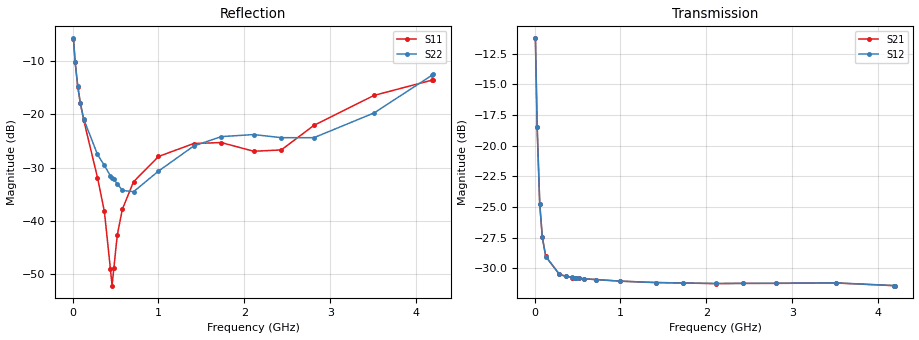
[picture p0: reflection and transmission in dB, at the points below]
! Integrated Device Technology
! Corporate Headquarters
! 6024 Silver Creek Valley Road
! San Jose, CA 95138  USA
! Phone:  1-408-284-8200
! Toll Free:  1-800-223-1366
! Webpage:  http://www.idt.com/
! Timing and RF Division
! 515 Groton Road, Suite 102
! Westford, MA 01886-6024
! Device:  F1950
! Description: 7-bit 0.25 dB Digital Step Attenuator
! Frequency:  150.0 -  4000.00 MHz
! Package:  4x4 mm Thin QFN Plastic Package: 24 pin
! Ports:  2 RF, 12 DC
!  Pin  1  = D0
!  Pin  2  = VDD
!  Pin  3  = Vmode
!  Pin  4  = GND
!  Pin  5  = RF1  =  Port 1
!  Pin  6  = GND
!  Pin  7  = GND
!  Pin  8  = GND
!  Pin  9  = GND
!  Pin 10  = GND
!  Pin 11  = GND
!  Pin 12  = GND
!  Pin 13  = GND
!  Pin 14  = RF2  =  Port 2
!  Pin 15  = GND
!  Pin 16  = LE
!  Pin 17  = CLK
!  Pin 18  = DATE
!  Pin 19  = D6
!  Pin 20  = D5
!  Pin 21  = D4
!  Pin 22  = D3
!  Pin 23  = D2
!  Pin 24  = D1
! State:  120
! Atten State:  30.00 dB
! Voltage:  +5.00 Volts
! Current:  Not Measured mA
! Data:  The device was measured on a the F195X evaluation board which has
!  individual transmission lines to the RF pins.  Data was collected
!  using a calibrated network analyzer.  The evaluation board was
!  de-embedded using a TRL calibration technique.
!  The reference plane is the edge of the package pin.
! Misc:  Board 2019
!  Action Tracker AT0250
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# GHz S dB R 50
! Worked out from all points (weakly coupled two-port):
!   420 points, 10 MHz to 4.2 GHz, reference 50 ohm
!   highest |S21| = -11.24 dB at 10 MHz (marker M1); lowest = -31.4 dB at 4.19 GHz (marker M2)
!   lowest |S11| = -52.2 dB at 460 MHz (marker M3), VSWR 1.00, Z = 49.8 - j0.108 ohm
!   |S11| at or under -10 dB: 28.84 MHz to end of sweep
!   |S22| runs from -34.8 to -5.7 dB; largest |S21 - S12| = 6.9e-05
!   S11 on the Smith chart (normalised r, x): 10 MHz: 2.05, -1.36; 30 MHz: 1.25, -0.68; 60 MHz: 1.10, -0.37; 290 MHz: 1.01, -0.05; 4.2 GHz: 0.68, +0.17
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0.01  -5.78 -28.3  -11.24 -39.9  -11.24 -39.9  -5.72 -29.3
0.03  -10.24 -52.8  -18.43 -66.2  -18.43 -66.2  -10.18 -54.2
0.06  -14.81 -65.1  -24.71 -61.0  -24.71 -61.0  -14.60 -66.6
0.09  -17.87 -70.5  -27.44 -49.8  -27.44 -49.8  -17.83 -70.9
0.13  -21.11 -73.1  -29.02 -38.7  -29.03 -38.7  -20.89 -74.4
0.29  -31.86 -74.2  -30.49 -21.1  -30.49 -21.0  -27.52 -83.6
0.37  -38.20 -74.1  -30.66 -17.9  -30.65 -17.9  -29.58 -87.7
0.44  -48.96 -108.2  -30.75 -16.2  -30.74 -16.2  -31.52 -94.0
0.46  -52.16 -153.9  -30.77 -15.8  -30.76 -15.8  -31.90 -97.3
0.48  -48.91 163.0  -30.78 -15.5  -30.78 -15.5  -32.20 -100.3
0.52  -42.70 145.4  -30.81 -15.0  -30.80 -15.0  -33.00 -103.9
0.58  -37.78 138.1  -30.85 -14.4  -30.85 -14.5  -34.28 -116.5
0.71  -32.64 139.3  -30.91 -13.8  -30.91 -13.8  -34.51 -141.3
1  -27.90 148.3  -31.04 -13.8  -31.04 -13.9  -30.65 178.7
1.41  -25.47 162.8  -31.15 -15.0  -31.16 -15.0  -25.93 160.3
1.73  -25.28 168.0  -31.19 -16.2  -31.19 -16.2  -24.17 151.9
2.11  -26.92 157.7  -31.24 -18.5  -31.23 -18.5  -23.78 142.0
2.43  -26.67 126.4  -31.22 -19.8  -31.22 -19.9  -24.37 131.3
2.81  -22.05 105.5  -31.22 -22.3  -31.21 -22.4  -24.37 115.9
3.51  -16.43 117.5  -31.19 -26.3  -31.18 -26.3  -19.72 113.2
4.19  -13.54 145.3  -31.41 -27.7  -31.40 -27.7  -12.58 127.2
4.2  -13.47 145.7  -31.40 -27.6  -31.40 -27.7  -12.47 127.1
